VERSION 5.7 ;
BUSBITCHARS "[]" ;
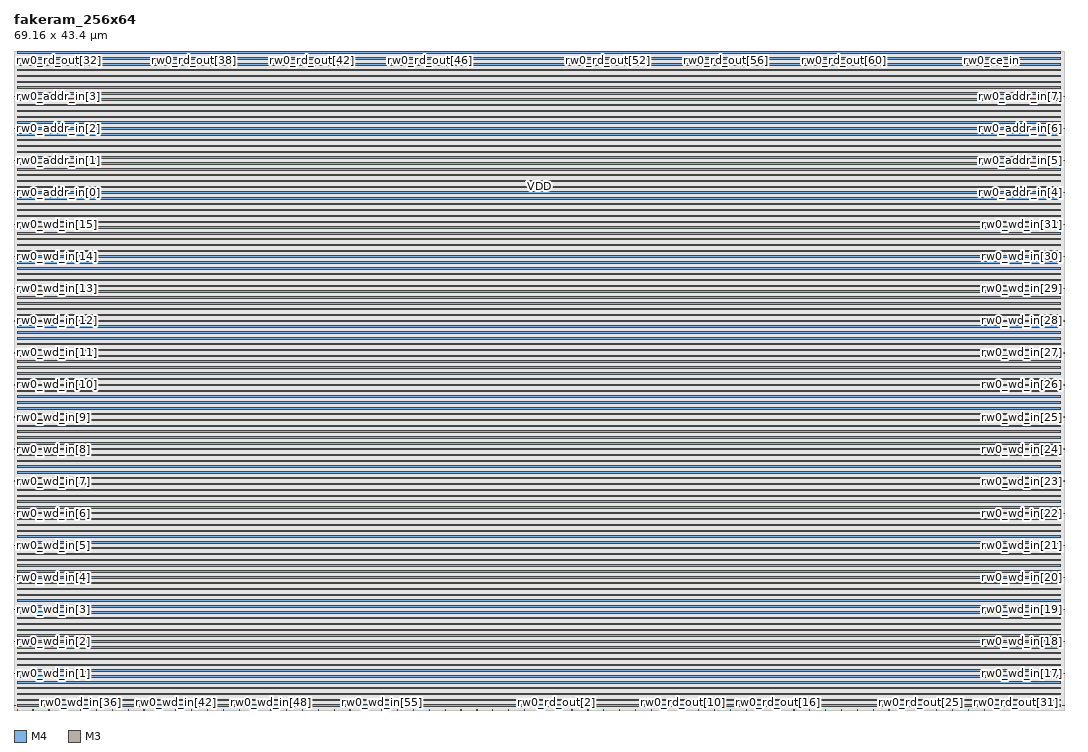
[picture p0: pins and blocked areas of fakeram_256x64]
MACRO fakeram_256x64
  FOREIGN fakeram_256x64 0 0 ;
  SYMMETRY X Y R90 ;
  SIZE 69.160 BY 43.400 ;
  CLASS BLOCK ;
  PIN rw0_wd_in[0]
    DIRECTION INPUT ;
    USE SIGNAL ;
    SHAPE ABUTMENT ;
    PORT
      LAYER M4 ;
      RECT 0.000 0.276 0.072 0.300 ;
    END
  END rw0_wd_in[0]
  PIN rw0_wd_in[1]
    DIRECTION INPUT ;
    USE SIGNAL ;
    SHAPE ABUTMENT ;
    PORT
      LAYER M4 ;
      RECT 0.000 2.388 0.072 2.412 ;
    END
  END rw0_wd_in[1]
  PIN rw0_wd_in[2]
    DIRECTION INPUT ;
    USE SIGNAL ;
    SHAPE ABUTMENT ;
    PORT
      LAYER M4 ;
      RECT 0.000 4.500 0.072 4.524 ;
    END
  END rw0_wd_in[2]
  PIN rw0_wd_in[3]
    DIRECTION INPUT ;
    USE SIGNAL ;
    SHAPE ABUTMENT ;
    PORT
      LAYER M4 ;
      RECT 0.000 6.612 0.072 6.636 ;
    END
  END rw0_wd_in[3]
  PIN rw0_wd_in[4]
    DIRECTION INPUT ;
    USE SIGNAL ;
    SHAPE ABUTMENT ;
    PORT
      LAYER M4 ;
      RECT 0.000 8.724 0.072 8.748 ;
    END
  END rw0_wd_in[4]
  PIN rw0_wd_in[5]
    DIRECTION INPUT ;
    USE SIGNAL ;
    SHAPE ABUTMENT ;
    PORT
      LAYER M4 ;
      RECT 0.000 10.836 0.072 10.860 ;
    END
  END rw0_wd_in[5]
  PIN rw0_wd_in[6]
    DIRECTION INPUT ;
    USE SIGNAL ;
    SHAPE ABUTMENT ;
    PORT
      LAYER M4 ;
      RECT 0.000 12.948 0.072 12.972 ;
    END
  END rw0_wd_in[6]
  PIN rw0_wd_in[7]
    DIRECTION INPUT ;
    USE SIGNAL ;
    SHAPE ABUTMENT ;
    PORT
      LAYER M4 ;
      RECT 0.000 15.060 0.072 15.084 ;
    END
  END rw0_wd_in[7]
  PIN rw0_wd_in[8]
    DIRECTION INPUT ;
    USE SIGNAL ;
    SHAPE ABUTMENT ;
    PORT
      LAYER M4 ;
      RECT 0.000 17.172 0.072 17.196 ;
    END
  END rw0_wd_in[8]
  PIN rw0_wd_in[9]
    DIRECTION INPUT ;
    USE SIGNAL ;
    SHAPE ABUTMENT ;
    PORT
      LAYER M4 ;
      RECT 0.000 19.284 0.072 19.308 ;
    END
  END rw0_wd_in[9]
  PIN rw0_wd_in[10]
    DIRECTION INPUT ;
    USE SIGNAL ;
    SHAPE ABUTMENT ;
    PORT
      LAYER M4 ;
      RECT 0.000 21.396 0.072 21.420 ;
    END
  END rw0_wd_in[10]
  PIN rw0_wd_in[11]
    DIRECTION INPUT ;
    USE SIGNAL ;
    SHAPE ABUTMENT ;
    PORT
      LAYER M4 ;
      RECT 0.000 23.508 0.072 23.532 ;
    END
  END rw0_wd_in[11]
  PIN rw0_wd_in[12]
    DIRECTION INPUT ;
    USE SIGNAL ;
    SHAPE ABUTMENT ;
    PORT
      LAYER M4 ;
      RECT 0.000 25.620 0.072 25.644 ;
    END
  END rw0_wd_in[12]
  PIN rw0_wd_in[13]
    DIRECTION INPUT ;
    USE SIGNAL ;
    SHAPE ABUTMENT ;
    PORT
      LAYER M4 ;
      RECT 0.000 27.732 0.072 27.756 ;
    END
  END rw0_wd_in[13]
  PIN rw0_wd_in[14]
    DIRECTION INPUT ;
    USE SIGNAL ;
    SHAPE ABUTMENT ;
    PORT
      LAYER M4 ;
      RECT 0.000 29.844 0.072 29.868 ;
    END
  END rw0_wd_in[14]
  PIN rw0_wd_in[15]
    DIRECTION INPUT ;
    USE SIGNAL ;
    SHAPE ABUTMENT ;
    PORT
      LAYER M4 ;
      RECT 0.000 31.956 0.072 31.980 ;
    END
  END rw0_wd_in[15]
  PIN rw0_wd_in[16]
    DIRECTION INPUT ;
    USE SIGNAL ;
    SHAPE ABUTMENT ;
    PORT
      LAYER M4 ;
      RECT 69.088 0.276 69.160 0.300 ;
    END
  END rw0_wd_in[16]
  PIN rw0_wd_in[17]
    DIRECTION INPUT ;
    USE SIGNAL ;
    SHAPE ABUTMENT ;
    PORT
      LAYER M4 ;
      RECT 69.088 2.388 69.160 2.412 ;
    END
  END rw0_wd_in[17]
  PIN rw0_wd_in[18]
    DIRECTION INPUT ;
    USE SIGNAL ;
    SHAPE ABUTMENT ;
    PORT
      LAYER M4 ;
      RECT 69.088 4.500 69.160 4.524 ;
    END
  END rw0_wd_in[18]
  PIN rw0_wd_in[19]
    DIRECTION INPUT ;
    USE SIGNAL ;
    SHAPE ABUTMENT ;
    PORT
      LAYER M4 ;
      RECT 69.088 6.612 69.160 6.636 ;
    END
  END rw0_wd_in[19]
  PIN rw0_wd_in[20]
    DIRECTION INPUT ;
    USE SIGNAL ;
    SHAPE ABUTMENT ;
    PORT
      LAYER M4 ;
      RECT 69.088 8.724 69.160 8.748 ;
    END
  END rw0_wd_in[20]
  PIN rw0_wd_in[21]
    DIRECTION INPUT ;
    USE SIGNAL ;
    SHAPE ABUTMENT ;
    PORT
      LAYER M4 ;
      RECT 69.088 10.836 69.160 10.860 ;
    END
  END rw0_wd_in[21]
  PIN rw0_wd_in[22]
    DIRECTION INPUT ;
    USE SIGNAL ;
    SHAPE ABUTMENT ;
    PORT
      LAYER M4 ;
      RECT 69.088 12.948 69.160 12.972 ;
    END
  END rw0_wd_in[22]
  PIN rw0_wd_in[23]
    DIRECTION INPUT ;
    USE SIGNAL ;
    SHAPE ABUTMENT ;
    PORT
      LAYER M4 ;
      RECT 69.088 15.060 69.160 15.084 ;
    END
  END rw0_wd_in[23]
  PIN rw0_wd_in[24]
    DIRECTION INPUT ;
    USE SIGNAL ;
    SHAPE ABUTMENT ;
    PORT
      LAYER M4 ;
      RECT 69.088 17.172 69.160 17.196 ;
    END
  END rw0_wd_in[24]
  PIN rw0_wd_in[25]
    DIRECTION INPUT ;
    USE SIGNAL ;
    SHAPE ABUTMENT ;
    PORT
      LAYER M4 ;
      RECT 69.088 19.284 69.160 19.308 ;
    END
  END rw0_wd_in[25]
  PIN rw0_wd_in[26]
    DIRECTION INPUT ;
    USE SIGNAL ;
    SHAPE ABUTMENT ;
    PORT
      LAYER M4 ;
      RECT 69.088 21.396 69.160 21.420 ;
    END
  END rw0_wd_in[26]
  PIN rw0_wd_in[27]
    DIRECTION INPUT ;
    USE SIGNAL ;
    SHAPE ABUTMENT ;
    PORT
      LAYER M4 ;
      RECT 69.088 23.508 69.160 23.532 ;
    END
  END rw0_wd_in[27]
  PIN rw0_wd_in[28]
    DIRECTION INPUT ;
    USE SIGNAL ;
    SHAPE ABUTMENT ;
    PORT
      LAYER M4 ;
      RECT 69.088 25.620 69.160 25.644 ;
    END
  END rw0_wd_in[28]
  PIN rw0_wd_in[29]
    DIRECTION INPUT ;
    USE SIGNAL ;
    SHAPE ABUTMENT ;
    PORT
      LAYER M4 ;
      RECT 69.088 27.732 69.160 27.756 ;
    END
  END rw0_wd_in[29]
  PIN rw0_wd_in[30]
    DIRECTION INPUT ;
    USE SIGNAL ;
    SHAPE ABUTMENT ;
    PORT
      LAYER M4 ;
      RECT 69.088 29.844 69.160 29.868 ;
    END
  END rw0_wd_in[30]
  PIN rw0_wd_in[31]
    DIRECTION INPUT ;
    USE SIGNAL ;
    SHAPE ABUTMENT ;
    PORT
      LAYER M4 ;
      RECT 69.088 31.956 69.160 31.980 ;
    END
  END rw0_wd_in[31]
  PIN rw0_wd_in[32]
    DIRECTION INPUT ;
    USE SIGNAL ;
    SHAPE ABUTMENT ;
    PORT
      LAYER M3 ;
      RECT 0.207 0.000 0.225 0.054 ;
    END
  END rw0_wd_in[32]
  PIN rw0_wd_in[33]
    DIRECTION INPUT ;
    USE SIGNAL ;
    SHAPE ABUTMENT ;
    PORT
      LAYER M3 ;
      RECT 1.251 0.000 1.269 0.054 ;
    END
  END rw0_wd_in[33]
  PIN rw0_wd_in[34]
    DIRECTION INPUT ;
    USE SIGNAL ;
    SHAPE ABUTMENT ;
    PORT
      LAYER M3 ;
      RECT 2.295 0.000 2.313 0.054 ;
    END
  END rw0_wd_in[34]
  PIN rw0_wd_in[35]
    DIRECTION INPUT ;
    USE SIGNAL ;
    SHAPE ABUTMENT ;
    PORT
      LAYER M3 ;
      RECT 3.339 0.000 3.357 0.054 ;
    END
  END rw0_wd_in[35]
  PIN rw0_wd_in[36]
    DIRECTION INPUT ;
    USE SIGNAL ;
    SHAPE ABUTMENT ;
    PORT
      LAYER M3 ;
      RECT 4.383 0.000 4.401 0.054 ;
    END
  END rw0_wd_in[36]
  PIN rw0_wd_in[37]
    DIRECTION INPUT ;
    USE SIGNAL ;
    SHAPE ABUTMENT ;
    PORT
      LAYER M3 ;
      RECT 5.427 0.000 5.445 0.054 ;
    END
  END rw0_wd_in[37]
  PIN rw0_wd_in[38]
    DIRECTION INPUT ;
    USE SIGNAL ;
    SHAPE ABUTMENT ;
    PORT
      LAYER M3 ;
      RECT 6.471 0.000 6.489 0.054 ;
    END
  END rw0_wd_in[38]
  PIN rw0_wd_in[39]
    DIRECTION INPUT ;
    USE SIGNAL ;
    SHAPE ABUTMENT ;
    PORT
      LAYER M3 ;
      RECT 7.515 0.000 7.533 0.054 ;
    END
  END rw0_wd_in[39]
  PIN rw0_wd_in[40]
    DIRECTION INPUT ;
    USE SIGNAL ;
    SHAPE ABUTMENT ;
    PORT
      LAYER M3 ;
      RECT 8.559 0.000 8.577 0.054 ;
    END
  END rw0_wd_in[40]
  PIN rw0_wd_in[41]
    DIRECTION INPUT ;
    USE SIGNAL ;
    SHAPE ABUTMENT ;
    PORT
      LAYER M3 ;
      RECT 9.603 0.000 9.621 0.054 ;
    END
  END rw0_wd_in[41]
  PIN rw0_wd_in[42]
    DIRECTION INPUT ;
    USE SIGNAL ;
    SHAPE ABUTMENT ;
    PORT
      LAYER M3 ;
      RECT 10.647 0.000 10.665 0.054 ;
    END
  END rw0_wd_in[42]
  PIN rw0_wd_in[43]
    DIRECTION INPUT ;
    USE SIGNAL ;
    SHAPE ABUTMENT ;
    PORT
      LAYER M3 ;
      RECT 11.691 0.000 11.709 0.054 ;
    END
  END rw0_wd_in[43]
  PIN rw0_wd_in[44]
    DIRECTION INPUT ;
    USE SIGNAL ;
    SHAPE ABUTMENT ;
    PORT
      LAYER M3 ;
      RECT 12.735 0.000 12.753 0.054 ;
    END
  END rw0_wd_in[44]
  PIN rw0_wd_in[45]
    DIRECTION INPUT ;
    USE SIGNAL ;
    SHAPE ABUTMENT ;
    PORT
      LAYER M3 ;
      RECT 13.779 0.000 13.797 0.054 ;
    END
  END rw0_wd_in[45]
  PIN rw0_wd_in[46]
    DIRECTION INPUT ;
    USE SIGNAL ;
    SHAPE ABUTMENT ;
    PORT
      LAYER M3 ;
      RECT 14.823 0.000 14.841 0.054 ;
    END
  END rw0_wd_in[46]
  PIN rw0_wd_in[47]
    DIRECTION INPUT ;
    USE SIGNAL ;
    SHAPE ABUTMENT ;
    PORT
      LAYER M3 ;
      RECT 15.867 0.000 15.885 0.054 ;
    END
  END rw0_wd_in[47]
  PIN rw0_wd_in[48]
    DIRECTION INPUT ;
    USE SIGNAL ;
    SHAPE ABUTMENT ;
    PORT
      LAYER M3 ;
      RECT 16.911 0.000 16.929 0.054 ;
    END
  END rw0_wd_in[48]
  PIN rw0_wd_in[49]
    DIRECTION INPUT ;
    USE SIGNAL ;
    SHAPE ABUTMENT ;
    PORT
      LAYER M3 ;
      RECT 17.955 0.000 17.973 0.054 ;
    END
  END rw0_wd_in[49]
  PIN rw0_wd_in[50]
    DIRECTION INPUT ;
    USE SIGNAL ;
    SHAPE ABUTMENT ;
    PORT
      LAYER M3 ;
      RECT 18.999 0.000 19.017 0.054 ;
    END
  END rw0_wd_in[50]
  PIN rw0_wd_in[51]
    DIRECTION INPUT ;
    USE SIGNAL ;
    SHAPE ABUTMENT ;
    PORT
      LAYER M3 ;
      RECT 20.043 0.000 20.061 0.054 ;
    END
  END rw0_wd_in[51]
  PIN rw0_wd_in[52]
    DIRECTION INPUT ;
    USE SIGNAL ;
    SHAPE ABUTMENT ;
    PORT
      LAYER M3 ;
      RECT 21.087 0.000 21.105 0.054 ;
    END
  END rw0_wd_in[52]
  PIN rw0_wd_in[53]
    DIRECTION INPUT ;
    USE SIGNAL ;
    SHAPE ABUTMENT ;
    PORT
      LAYER M3 ;
      RECT 22.131 0.000 22.149 0.054 ;
    END
  END rw0_wd_in[53]
  PIN rw0_wd_in[54]
    DIRECTION INPUT ;
    USE SIGNAL ;
    SHAPE ABUTMENT ;
    PORT
      LAYER M3 ;
      RECT 23.175 0.000 23.193 0.054 ;
    END
  END rw0_wd_in[54]
  PIN rw0_wd_in[55]
    DIRECTION INPUT ;
    USE SIGNAL ;
    SHAPE ABUTMENT ;
    PORT
      LAYER M3 ;
      RECT 24.219 0.000 24.237 0.054 ;
    END
  END rw0_wd_in[55]
  PIN rw0_wd_in[56]
    DIRECTION INPUT ;
    USE SIGNAL ;
    SHAPE ABUTMENT ;
    PORT
      LAYER M3 ;
      RECT 25.263 0.000 25.281 0.054 ;
    END
  END rw0_wd_in[56]
  PIN rw0_wd_in[57]
    DIRECTION INPUT ;
    USE SIGNAL ;
    SHAPE ABUTMENT ;
    PORT
      LAYER M3 ;
      RECT 26.307 0.000 26.325 0.054 ;
    END
  END rw0_wd_in[57]
  PIN rw0_wd_in[58]
    DIRECTION INPUT ;
    USE SIGNAL ;
    SHAPE ABUTMENT ;
    PORT
      LAYER M3 ;
      RECT 27.351 0.000 27.369 0.054 ;
    END
  END rw0_wd_in[58]
  PIN rw0_wd_in[59]
    DIRECTION INPUT ;
    USE SIGNAL ;
    SHAPE ABUTMENT ;
    PORT
      LAYER M3 ;
      RECT 28.395 0.000 28.413 0.054 ;
    END
  END rw0_wd_in[59]
  PIN rw0_wd_in[60]
    DIRECTION INPUT ;
    USE SIGNAL ;
    SHAPE ABUTMENT ;
    PORT
      LAYER M3 ;
      RECT 29.439 0.000 29.457 0.054 ;
    END
  END rw0_wd_in[60]
  PIN rw0_wd_in[61]
    DIRECTION INPUT ;
    USE SIGNAL ;
    SHAPE ABUTMENT ;
    PORT
      LAYER M3 ;
      RECT 30.483 0.000 30.501 0.054 ;
    END
  END rw0_wd_in[61]
  PIN rw0_wd_in[62]
    DIRECTION INPUT ;
    USE SIGNAL ;
    SHAPE ABUTMENT ;
    PORT
      LAYER M3 ;
      RECT 31.527 0.000 31.545 0.054 ;
    END
  END rw0_wd_in[62]
  PIN rw0_wd_in[63]
    DIRECTION INPUT ;
    USE SIGNAL ;
    SHAPE ABUTMENT ;
    PORT
      LAYER M3 ;
      RECT 32.571 0.000 32.589 0.054 ;
    END
  END rw0_wd_in[63]
  PIN rw0_rd_out[0]
    DIRECTION OUTPUT ;
    USE SIGNAL ;
    SHAPE ABUTMENT ;
    PORT
      LAYER M3 ;
      RECT 33.615 0.000 33.633 0.054 ;
    END
  END rw0_rd_out[0]
  PIN rw0_rd_out[1]
    DIRECTION OUTPUT ;
    USE SIGNAL ;
    SHAPE ABUTMENT ;
    PORT
      LAYER M3 ;
      RECT 34.659 0.000 34.677 0.054 ;
    END
  END rw0_rd_out[1]
  PIN rw0_rd_out[2]
    DIRECTION OUTPUT ;
    USE SIGNAL ;
    SHAPE ABUTMENT ;
    PORT
      LAYER M3 ;
      RECT 35.703 0.000 35.721 0.054 ;
    END
  END rw0_rd_out[2]
  PIN rw0_rd_out[3]
    DIRECTION OUTPUT ;
    USE SIGNAL ;
    SHAPE ABUTMENT ;
    PORT
      LAYER M3 ;
      RECT 36.747 0.000 36.765 0.054 ;
    END
  END rw0_rd_out[3]
  PIN rw0_rd_out[4]
    DIRECTION OUTPUT ;
    USE SIGNAL ;
    SHAPE ABUTMENT ;
    PORT
      LAYER M3 ;
      RECT 37.791 0.000 37.809 0.054 ;
    END
  END rw0_rd_out[4]
  PIN rw0_rd_out[5]
    DIRECTION OUTPUT ;
    USE SIGNAL ;
    SHAPE ABUTMENT ;
    PORT
      LAYER M3 ;
      RECT 38.835 0.000 38.853 0.054 ;
    END
  END rw0_rd_out[5]
  PIN rw0_rd_out[6]
    DIRECTION OUTPUT ;
    USE SIGNAL ;
    SHAPE ABUTMENT ;
    PORT
      LAYER M3 ;
      RECT 39.879 0.000 39.897 0.054 ;
    END
  END rw0_rd_out[6]
  PIN rw0_rd_out[7]
    DIRECTION OUTPUT ;
    USE SIGNAL ;
    SHAPE ABUTMENT ;
    PORT
      LAYER M3 ;
      RECT 40.923 0.000 40.941 0.054 ;
    END
  END rw0_rd_out[7]
  PIN rw0_rd_out[8]
    DIRECTION OUTPUT ;
    USE SIGNAL ;
    SHAPE ABUTMENT ;
    PORT
      LAYER M3 ;
      RECT 41.967 0.000 41.985 0.054 ;
    END
  END rw0_rd_out[8]
  PIN rw0_rd_out[9]
    DIRECTION OUTPUT ;
    USE SIGNAL ;
    SHAPE ABUTMENT ;
    PORT
      LAYER M3 ;
      RECT 43.011 0.000 43.029 0.054 ;
    END
  END rw0_rd_out[9]
  PIN rw0_rd_out[10]
    DIRECTION OUTPUT ;
    USE SIGNAL ;
    SHAPE ABUTMENT ;
    PORT
      LAYER M3 ;
      RECT 44.055 0.000 44.073 0.054 ;
    END
  END rw0_rd_out[10]
  PIN rw0_rd_out[11]
    DIRECTION OUTPUT ;
    USE SIGNAL ;
    SHAPE ABUTMENT ;
    PORT
      LAYER M3 ;
      RECT 45.099 0.000 45.117 0.054 ;
    END
  END rw0_rd_out[11]
  PIN rw0_rd_out[12]
    DIRECTION OUTPUT ;
    USE SIGNAL ;
    SHAPE ABUTMENT ;
    PORT
      LAYER M3 ;
      RECT 46.143 0.000 46.161 0.054 ;
    END
  END rw0_rd_out[12]
  PIN rw0_rd_out[13]
    DIRECTION OUTPUT ;
    USE SIGNAL ;
    SHAPE ABUTMENT ;
    PORT
      LAYER M3 ;
      RECT 47.187 0.000 47.205 0.054 ;
    END
  END rw0_rd_out[13]
  PIN rw0_rd_out[14]
    DIRECTION OUTPUT ;
    USE SIGNAL ;
    SHAPE ABUTMENT ;
    PORT
      LAYER M3 ;
      RECT 48.231 0.000 48.249 0.054 ;
    END
  END rw0_rd_out[14]
  PIN rw0_rd_out[15]
    DIRECTION OUTPUT ;
    USE SIGNAL ;
    SHAPE ABUTMENT ;
    PORT
      LAYER M3 ;
      RECT 49.275 0.000 49.293 0.054 ;
    END
  END rw0_rd_out[15]
  PIN rw0_rd_out[16]
    DIRECTION OUTPUT ;
    USE SIGNAL ;
    SHAPE ABUTMENT ;
    PORT
      LAYER M3 ;
      RECT 50.319 0.000 50.337 0.054 ;
    END
  END rw0_rd_out[16]
  PIN rw0_rd_out[17]
    DIRECTION OUTPUT ;
    USE SIGNAL ;
    SHAPE ABUTMENT ;
    PORT
      LAYER M3 ;
      RECT 51.363 0.000 51.381 0.054 ;
    END
  END rw0_rd_out[17]
  PIN rw0_rd_out[18]
    DIRECTION OUTPUT ;
    USE SIGNAL ;
    SHAPE ABUTMENT ;
    PORT
      LAYER M3 ;
      RECT 52.407 0.000 52.425 0.054 ;
    END
  END rw0_rd_out[18]
  PIN rw0_rd_out[19]
    DIRECTION OUTPUT ;
    USE SIGNAL ;
    SHAPE ABUTMENT ;
    PORT
      LAYER M3 ;
      RECT 53.451 0.000 53.469 0.054 ;
    END
  END rw0_rd_out[19]
  PIN rw0_rd_out[20]
    DIRECTION OUTPUT ;
    USE SIGNAL ;
    SHAPE ABUTMENT ;
    PORT
      LAYER M3 ;
      RECT 54.495 0.000 54.513 0.054 ;
    END
  END rw0_rd_out[20]
  PIN rw0_rd_out[21]
    DIRECTION OUTPUT ;
    USE SIGNAL ;
    SHAPE ABUTMENT ;
    PORT
      LAYER M3 ;
      RECT 55.539 0.000 55.557 0.054 ;
    END
  END rw0_rd_out[21]
  PIN rw0_rd_out[22]
    DIRECTION OUTPUT ;
    USE SIGNAL ;
    SHAPE ABUTMENT ;
    PORT
      LAYER M3 ;
      RECT 56.583 0.000 56.601 0.054 ;
    END
  END rw0_rd_out[22]
  PIN rw0_rd_out[23]
    DIRECTION OUTPUT ;
    USE SIGNAL ;
    SHAPE ABUTMENT ;
    PORT
      LAYER M3 ;
      RECT 57.627 0.000 57.645 0.054 ;
    END
  END rw0_rd_out[23]
  PIN rw0_rd_out[24]
    DIRECTION OUTPUT ;
    USE SIGNAL ;
    SHAPE ABUTMENT ;
    PORT
      LAYER M3 ;
      RECT 58.671 0.000 58.689 0.054 ;
    END
  END rw0_rd_out[24]
  PIN rw0_rd_out[25]
    DIRECTION OUTPUT ;
    USE SIGNAL ;
    SHAPE ABUTMENT ;
    PORT
      LAYER M3 ;
      RECT 59.715 0.000 59.733 0.054 ;
    END
  END rw0_rd_out[25]
  PIN rw0_rd_out[26]
    DIRECTION OUTPUT ;
    USE SIGNAL ;
    SHAPE ABUTMENT ;
    PORT
      LAYER M3 ;
      RECT 60.759 0.000 60.777 0.054 ;
    END
  END rw0_rd_out[26]
  PIN rw0_rd_out[27]
    DIRECTION OUTPUT ;
    USE SIGNAL ;
    SHAPE ABUTMENT ;
    PORT
      LAYER M3 ;
      RECT 61.803 0.000 61.821 0.054 ;
    END
  END rw0_rd_out[27]
  PIN rw0_rd_out[28]
    DIRECTION OUTPUT ;
    USE SIGNAL ;
    SHAPE ABUTMENT ;
    PORT
      LAYER M3 ;
      RECT 62.847 0.000 62.865 0.054 ;
    END
  END rw0_rd_out[28]
  PIN rw0_rd_out[29]
    DIRECTION OUTPUT ;
    USE SIGNAL ;
    SHAPE ABUTMENT ;
    PORT
      LAYER M3 ;
      RECT 63.891 0.000 63.909 0.054 ;
    END
  END rw0_rd_out[29]
  PIN rw0_rd_out[30]
    DIRECTION OUTPUT ;
    USE SIGNAL ;
    SHAPE ABUTMENT ;
    PORT
      LAYER M3 ;
      RECT 64.935 0.000 64.953 0.054 ;
    END
  END rw0_rd_out[30]
  PIN rw0_rd_out[31]
    DIRECTION OUTPUT ;
    USE SIGNAL ;
    SHAPE ABUTMENT ;
    PORT
      LAYER M3 ;
      RECT 65.979 0.000 65.997 0.054 ;
    END
  END rw0_rd_out[31]
  PIN rw0_rd_out[32]
    DIRECTION OUTPUT ;
    USE SIGNAL ;
    SHAPE ABUTMENT ;
    PORT
      LAYER M3 ;
      RECT 0.207 43.346 0.225 43.400 ;
    END
  END rw0_rd_out[32]
  PIN rw0_rd_out[33]
    DIRECTION OUTPUT ;
    USE SIGNAL ;
    SHAPE ABUTMENT ;
    PORT
      LAYER M3 ;
      RECT 2.151 43.346 2.169 43.400 ;
    END
  END rw0_rd_out[33]
  PIN rw0_rd_out[34]
    DIRECTION OUTPUT ;
    USE SIGNAL ;
    SHAPE ABUTMENT ;
    PORT
      LAYER M3 ;
      RECT 4.095 43.346 4.113 43.400 ;
    END
  END rw0_rd_out[34]
  PIN rw0_rd_out[35]
    DIRECTION OUTPUT ;
    USE SIGNAL ;
    SHAPE ABUTMENT ;
    PORT
      LAYER M3 ;
      RECT 6.039 43.346 6.057 43.400 ;
    END
  END rw0_rd_out[35]
  PIN rw0_rd_out[36]
    DIRECTION OUTPUT ;
    USE SIGNAL ;
    SHAPE ABUTMENT ;
    PORT
      LAYER M3 ;
      RECT 7.983 43.346 8.001 43.400 ;
    END
  END rw0_rd_out[36]
  PIN rw0_rd_out[37]
    DIRECTION OUTPUT ;
    USE SIGNAL ;
    SHAPE ABUTMENT ;
    PORT
      LAYER M3 ;
      RECT 9.927 43.346 9.945 43.400 ;
    END
  END rw0_rd_out[37]
  PIN rw0_rd_out[38]
    DIRECTION OUTPUT ;
    USE SIGNAL ;
    SHAPE ABUTMENT ;
    PORT
      LAYER M3 ;
      RECT 11.871 43.346 11.889 43.400 ;
    END
  END rw0_rd_out[38]
  PIN rw0_rd_out[39]
    DIRECTION OUTPUT ;
    USE SIGNAL ;
    SHAPE ABUTMENT ;
    PORT
      LAYER M3 ;
      RECT 13.815 43.346 13.833 43.400 ;
    END
  END rw0_rd_out[39]
  PIN rw0_rd_out[40]
    DIRECTION OUTPUT ;
    USE SIGNAL ;
    SHAPE ABUTMENT ;
    PORT
      LAYER M3 ;
      RECT 15.759 43.346 15.777 43.400 ;
    END
  END rw0_rd_out[40]
  PIN rw0_rd_out[41]
    DIRECTION OUTPUT ;
    USE SIGNAL ;
    SHAPE ABUTMENT ;
    PORT
      LAYER M3 ;
      RECT 17.703 43.346 17.721 43.400 ;
    END
  END rw0_rd_out[41]
  PIN rw0_rd_out[42]
    DIRECTION OUTPUT ;
    USE SIGNAL ;
    SHAPE ABUTMENT ;
    PORT
      LAYER M3 ;
      RECT 19.647 43.346 19.665 43.400 ;
    END
  END rw0_rd_out[42]
  PIN rw0_rd_out[43]
    DIRECTION OUTPUT ;
    USE SIGNAL ;
    SHAPE ABUTMENT ;
    PORT
      LAYER M3 ;
      RECT 21.591 43.346 21.609 43.400 ;
    END
  END rw0_rd_out[43]
  PIN rw0_rd_out[44]
    DIRECTION OUTPUT ;
    USE SIGNAL ;
    SHAPE ABUTMENT ;
    PORT
      LAYER M3 ;
      RECT 23.535 43.346 23.553 43.400 ;
    END
  END rw0_rd_out[44]
  PIN rw0_rd_out[45]
    DIRECTION OUTPUT ;
    USE SIGNAL ;
    SHAPE ABUTMENT ;
    PORT
      LAYER M3 ;
      RECT 25.479 43.346 25.497 43.400 ;
    END
  END rw0_rd_out[45]
  PIN rw0_rd_out[46]
    DIRECTION OUTPUT ;
    USE SIGNAL ;
    SHAPE ABUTMENT ;
    PORT
      LAYER M3 ;
      RECT 27.423 43.346 27.441 43.400 ;
    END
  END rw0_rd_out[46]
  PIN rw0_rd_out[47]
    DIRECTION OUTPUT ;
    USE SIGNAL ;
    SHAPE ABUTMENT ;
    PORT
      LAYER M3 ;
      RECT 29.367 43.346 29.385 43.400 ;
    END
  END rw0_rd_out[47]
  PIN rw0_rd_out[48]
    DIRECTION OUTPUT ;
    USE SIGNAL ;
    SHAPE ABUTMENT ;
    PORT
      LAYER M3 ;
      RECT 31.311 43.346 31.329 43.400 ;
    END
  END rw0_rd_out[48]
  PIN rw0_rd_out[49]
    DIRECTION OUTPUT ;
    USE SIGNAL ;
    SHAPE ABUTMENT ;
    PORT
      LAYER M3 ;
      RECT 33.255 43.346 33.273 43.400 ;
    END
  END rw0_rd_out[49]
  PIN rw0_rd_out[50]
    DIRECTION OUTPUT ;
    USE SIGNAL ;
    SHAPE ABUTMENT ;
    PORT
      LAYER M3 ;
      RECT 35.199 43.346 35.217 43.400 ;
    END
  END rw0_rd_out[50]
  PIN rw0_rd_out[51]
    DIRECTION OUTPUT ;
    USE SIGNAL ;
    SHAPE ABUTMENT ;
    PORT
      LAYER M3 ;
      RECT 37.143 43.346 37.161 43.400 ;
    END
  END rw0_rd_out[51]
  PIN rw0_rd_out[52]
    DIRECTION OUTPUT ;
    USE SIGNAL ;
    SHAPE ABUTMENT ;
    PORT
      LAYER M3 ;
      RECT 39.087 43.346 39.105 43.400 ;
    END
  END rw0_rd_out[52]
  PIN rw0_rd_out[53]
    DIRECTION OUTPUT ;
    USE SIGNAL ;
    SHAPE ABUTMENT ;
    PORT
      LAYER M3 ;
      RECT 41.031 43.346 41.049 43.400 ;
    END
  END rw0_rd_out[53]
  PIN rw0_rd_out[54]
    DIRECTION OUTPUT ;
    USE SIGNAL ;
    SHAPE ABUTMENT ;
    PORT
      LAYER M3 ;
      RECT 42.975 43.346 42.993 43.400 ;
    END
  END rw0_rd_out[54]
  PIN rw0_rd_out[55]
    DIRECTION OUTPUT ;
    USE SIGNAL ;
    SHAPE ABUTMENT ;
    PORT
      LAYER M3 ;
      RECT 44.919 43.346 44.937 43.400 ;
    END
  END rw0_rd_out[55]
  PIN rw0_rd_out[56]
    DIRECTION OUTPUT ;
    USE SIGNAL ;
    SHAPE ABUTMENT ;
    PORT
      LAYER M3 ;
      RECT 46.863 43.346 46.881 43.400 ;
    END
  END rw0_rd_out[56]
  PIN rw0_rd_out[57]
    DIRECTION OUTPUT ;
    USE SIGNAL ;
    SHAPE ABUTMENT ;
    PORT
      LAYER M3 ;
      RECT 48.807 43.346 48.825 43.400 ;
    END
  END rw0_rd_out[57]
  PIN rw0_rd_out[58]
    DIRECTION OUTPUT ;
    USE SIGNAL ;
    SHAPE ABUTMENT ;
    PORT
      LAYER M3 ;
      RECT 50.751 43.346 50.769 43.400 ;
    END
  END rw0_rd_out[58]
  PIN rw0_rd_out[59]
    DIRECTION OUTPUT ;
    USE SIGNAL ;
    SHAPE ABUTMENT ;
    PORT
      LAYER M3 ;
      RECT 52.695 43.346 52.713 43.400 ;
    END
  END rw0_rd_out[59]
  PIN rw0_rd_out[60]
    DIRECTION OUTPUT ;
    USE SIGNAL ;
    SHAPE ABUTMENT ;
    PORT
      LAYER M3 ;
      RECT 54.639 43.346 54.657 43.400 ;
    END
  END rw0_rd_out[60]
  PIN rw0_rd_out[61]
    DIRECTION OUTPUT ;
    USE SIGNAL ;
    SHAPE ABUTMENT ;
    PORT
      LAYER M3 ;
      RECT 56.583 43.346 56.601 43.400 ;
    END
  END rw0_rd_out[61]
  PIN rw0_rd_out[62]
    DIRECTION OUTPUT ;
    USE SIGNAL ;
    SHAPE ABUTMENT ;
    PORT
      LAYER M3 ;
      RECT 58.527 43.346 58.545 43.400 ;
    END
  END rw0_rd_out[62]
  PIN rw0_rd_out[63]
    DIRECTION OUTPUT ;
    USE SIGNAL ;
    SHAPE ABUTMENT ;
    PORT
      LAYER M3 ;
      RECT 60.471 43.346 60.489 43.400 ;
    END
  END rw0_rd_out[63]
  PIN rw0_addr_in[0]
    DIRECTION INPUT ;
    USE SIGNAL ;
    SHAPE ABUTMENT ;
    PORT
      LAYER M4 ;
      RECT 0.000 34.068 0.072 34.092 ;
    END
  END rw0_addr_in[0]
  PIN rw0_addr_in[1]
    DIRECTION INPUT ;
    USE SIGNAL ;
    SHAPE ABUTMENT ;
    PORT
      LAYER M4 ;
      RECT 0.000 36.180 0.072 36.204 ;
    END
  END rw0_addr_in[1]
  PIN rw0_addr_in[2]
    DIRECTION INPUT ;
    USE SIGNAL ;
    SHAPE ABUTMENT ;
    PORT
      LAYER M4 ;
      RECT 0.000 38.292 0.072 38.316 ;
    END
  END rw0_addr_in[2]
  PIN rw0_addr_in[3]
    DIRECTION INPUT ;
    USE SIGNAL ;
    SHAPE ABUTMENT ;
    PORT
      LAYER M4 ;
      RECT 0.000 40.404 0.072 40.428 ;
    END
  END rw0_addr_in[3]
  PIN rw0_addr_in[4]
    DIRECTION INPUT ;
    USE SIGNAL ;
    SHAPE ABUTMENT ;
    PORT
      LAYER M4 ;
      RECT 69.088 34.068 69.160 34.092 ;
    END
  END rw0_addr_in[4]
  PIN rw0_addr_in[5]
    DIRECTION INPUT ;
    USE SIGNAL ;
    SHAPE ABUTMENT ;
    PORT
      LAYER M4 ;
      RECT 69.088 36.180 69.160 36.204 ;
    END
  END rw0_addr_in[5]
  PIN rw0_addr_in[6]
    DIRECTION INPUT ;
    USE SIGNAL ;
    SHAPE ABUTMENT ;
    PORT
      LAYER M4 ;
      RECT 69.088 38.292 69.160 38.316 ;
    END
  END rw0_addr_in[6]
  PIN rw0_addr_in[7]
    DIRECTION INPUT ;
    USE SIGNAL ;
    SHAPE ABUTMENT ;
    PORT
      LAYER M4 ;
      RECT 69.088 40.404 69.160 40.428 ;
    END
  END rw0_addr_in[7]
  PIN rw0_we_in
    DIRECTION INPUT ;
    USE SIGNAL ;
    SHAPE ABUTMENT ;
    PORT
      LAYER M3 ;
      RECT 62.415 43.346 62.433 43.400 ;
    END
  END rw0_we_in
  PIN rw0_ce_in
    DIRECTION INPUT ;
    USE SIGNAL ;
    SHAPE ABUTMENT ;
    PORT
      LAYER M3 ;
      RECT 64.359 43.346 64.377 43.400 ;
    END
  END rw0_ce_in
  PIN rw0_clk
    DIRECTION INPUT ;
    USE SIGNAL ;
    SHAPE ABUTMENT ;
    PORT
      LAYER M3 ;
      RECT 66.303 43.346 66.321 43.400 ;
    END
  END rw0_clk
  PIN VSS
    DIRECTION INOUT ;
    USE GROUND ;
    PORT
      LAYER M4 ;
      RECT 0.216 0.240 68.944 0.336 ;
      RECT 0.216 1.008 68.944 1.104 ;
      RECT 0.216 1.776 68.944 1.872 ;
      RECT 0.216 2.544 68.944 2.640 ;
      RECT 0.216 3.312 68.944 3.408 ;
      RECT 0.216 4.080 68.944 4.176 ;
      RECT 0.216 4.848 68.944 4.944 ;
      RECT 0.216 5.616 68.944 5.712 ;
      RECT 0.216 6.384 68.944 6.480 ;
      RECT 0.216 7.152 68.944 7.248 ;
      RECT 0.216 7.920 68.944 8.016 ;
      RECT 0.216 8.688 68.944 8.784 ;
      RECT 0.216 9.456 68.944 9.552 ;
      RECT 0.216 10.224 68.944 10.320 ;
      RECT 0.216 10.992 68.944 11.088 ;
      RECT 0.216 11.760 68.944 11.856 ;
      RECT 0.216 12.528 68.944 12.624 ;
      RECT 0.216 13.296 68.944 13.392 ;
      RECT 0.216 14.064 68.944 14.160 ;
      RECT 0.216 14.832 68.944 14.928 ;
      RECT 0.216 15.600 68.944 15.696 ;
      RECT 0.216 16.368 68.944 16.464 ;
      RECT 0.216 17.136 68.944 17.232 ;
      RECT 0.216 17.904 68.944 18.000 ;
      RECT 0.216 18.672 68.944 18.768 ;
      RECT 0.216 19.440 68.944 19.536 ;
      RECT 0.216 20.208 68.944 20.304 ;
      RECT 0.216 20.976 68.944 21.072 ;
      RECT 0.216 21.744 68.944 21.840 ;
      RECT 0.216 22.512 68.944 22.608 ;
      RECT 0.216 23.280 68.944 23.376 ;
      RECT 0.216 24.048 68.944 24.144 ;
      RECT 0.216 24.816 68.944 24.912 ;
      RECT 0.216 25.584 68.944 25.680 ;
      RECT 0.216 26.352 68.944 26.448 ;
      RECT 0.216 27.120 68.944 27.216 ;
      RECT 0.216 27.888 68.944 27.984 ;
      RECT 0.216 28.656 68.944 28.752 ;
      RECT 0.216 29.424 68.944 29.520 ;
      RECT 0.216 30.192 68.944 30.288 ;
      RECT 0.216 30.960 68.944 31.056 ;
      RECT 0.216 31.728 68.944 31.824 ;
      RECT 0.216 32.496 68.944 32.592 ;
      RECT 0.216 33.264 68.944 33.360 ;
      RECT 0.216 34.032 68.944 34.128 ;
      RECT 0.216 34.800 68.944 34.896 ;
      RECT 0.216 35.568 68.944 35.664 ;
      RECT 0.216 36.336 68.944 36.432 ;
      RECT 0.216 37.104 68.944 37.200 ;
      RECT 0.216 37.872 68.944 37.968 ;
      RECT 0.216 38.640 68.944 38.736 ;
      RECT 0.216 39.408 68.944 39.504 ;
      RECT 0.216 40.176 68.944 40.272 ;
      RECT 0.216 40.944 68.944 41.040 ;
      RECT 0.216 41.712 68.944 41.808 ;
      RECT 0.216 42.480 68.944 42.576 ;
      RECT 0.216 43.248 68.944 43.344 ;
    END
  END VSS
  PIN VDD
    DIRECTION INOUT ;
    USE POWER ;
    PORT
      LAYER M4 ;
      RECT 0.216 0.624 68.944 0.720 ;
      RECT 0.216 1.392 68.944 1.488 ;
      RECT 0.216 2.160 68.944 2.256 ;
      RECT 0.216 2.928 68.944 3.024 ;
      RECT 0.216 3.696 68.944 3.792 ;
      RECT 0.216 4.464 68.944 4.560 ;
      RECT 0.216 5.232 68.944 5.328 ;
      RECT 0.216 6.000 68.944 6.096 ;
      RECT 0.216 6.768 68.944 6.864 ;
      RECT 0.216 7.536 68.944 7.632 ;
      RECT 0.216 8.304 68.944 8.400 ;
      RECT 0.216 9.072 68.944 9.168 ;
      RECT 0.216 9.840 68.944 9.936 ;
      RECT 0.216 10.608 68.944 10.704 ;
      RECT 0.216 11.376 68.944 11.472 ;
      RECT 0.216 12.144 68.944 12.240 ;
      RECT 0.216 12.912 68.944 13.008 ;
      RECT 0.216 13.680 68.944 13.776 ;
      RECT 0.216 14.448 68.944 14.544 ;
      RECT 0.216 15.216 68.944 15.312 ;
      RECT 0.216 15.984 68.944 16.080 ;
      RECT 0.216 16.752 68.944 16.848 ;
      RECT 0.216 17.520 68.944 17.616 ;
      RECT 0.216 18.288 68.944 18.384 ;
      RECT 0.216 19.056 68.944 19.152 ;
      RECT 0.216 19.824 68.944 19.920 ;
      RECT 0.216 20.592 68.944 20.688 ;
      RECT 0.216 21.360 68.944 21.456 ;
      RECT 0.216 22.128 68.944 22.224 ;
      RECT 0.216 22.896 68.944 22.992 ;
      RECT 0.216 23.664 68.944 23.760 ;
      RECT 0.216 24.432 68.944 24.528 ;
      RECT 0.216 25.200 68.944 25.296 ;
      RECT 0.216 25.968 68.944 26.064 ;
      RECT 0.216 26.736 68.944 26.832 ;
      RECT 0.216 27.504 68.944 27.600 ;
      RECT 0.216 28.272 68.944 28.368 ;
      RECT 0.216 29.040 68.944 29.136 ;
      RECT 0.216 29.808 68.944 29.904 ;
      RECT 0.216 30.576 68.944 30.672 ;
      RECT 0.216 31.344 68.944 31.440 ;
      RECT 0.216 32.112 68.944 32.208 ;
      RECT 0.216 32.880 68.944 32.976 ;
      RECT 0.216 33.648 68.944 33.744 ;
      RECT 0.216 34.416 68.944 34.512 ;
      RECT 0.216 35.184 68.944 35.280 ;
      RECT 0.216 35.952 68.944 36.048 ;
      RECT 0.216 36.720 68.944 36.816 ;
      RECT 0.216 37.488 68.944 37.584 ;
      RECT 0.216 38.256 68.944 38.352 ;
      RECT 0.216 39.024 68.944 39.120 ;
      RECT 0.216 39.792 68.944 39.888 ;
      RECT 0.216 40.560 68.944 40.656 ;
      RECT 0.216 41.328 68.944 41.424 ;
      RECT 0.216 42.096 68.944 42.192 ;
      RECT 0.216 42.864 68.944 42.960 ;
    END
  END VDD
  OBS
    LAYER M1 ;
    RECT 0 0 69.160 43.400 ;
    LAYER M2 ;
    RECT 0 0 69.160 43.400 ;
    LAYER M3 ;
    RECT 0 0 69.160 43.400 ;
    LAYER M4 ;
    RECT 0 0 69.160 43.400 ;
  END
END fakeram_256x64

END LIBRARY
